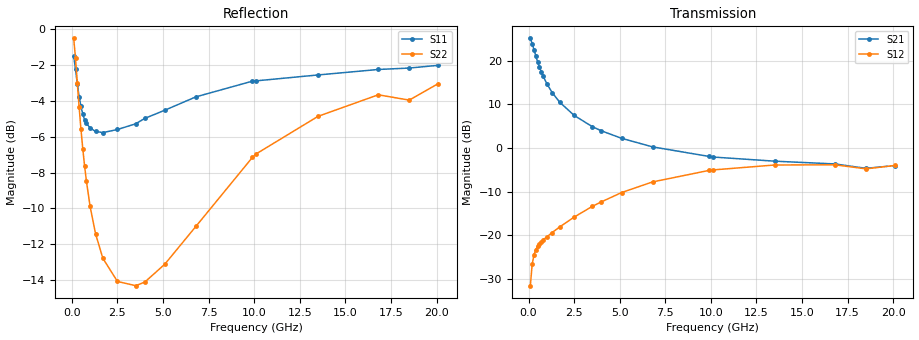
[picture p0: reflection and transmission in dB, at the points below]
!  Infineon Technologies AG
! BFR380L3 , PF131585-7, No.6, Th 09.10.01, soldered on pcb-board, measured with PP GSG850
!  Vce=4.0 V,  Ic=6.0 mA
! Common Emitter S-Parameters:  15. November 2001
#  GHz  S  MA  R  50
! f  S11  S21  S12  S22
! GHz  Mag  Ang  Mag  Ang  Mag  Ang  Mag  Ang
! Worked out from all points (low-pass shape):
!   201 points, 100 MHz to 20.1 GHz, reference 50 ohm
!   highest |S21| = 25.08 dB at 100 MHz (marker M1); lowest = -4.7 dB at 18.5 GHz (marker M2)
!   |S21| within 3 dB of the highest: start of sweep to 327.2 MHz
!   lowest |S11| = -5.8 dB at 1.7 GHz (marker M3), VSWR 3.12, Z = 16.1 - j1.68 ohm
!   |S11| at or under -10 dB: nowhere
!   |S22| runs from -14.4 to -0.5 dB; largest |S21 - S12| = 18
!   S11 on the Smith chart (normalised r, x): 100 MHz: 1.15, -3.32; 400 MHz: 0.38, -0.84; 1 GHz: 0.33, -0.25; 4 GHz: 0.31, +0.34; 9.9 GHz: 0.39, +1.12; 20.1 GHz: 0.95, +2.53
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0.1  0.8396 -30.4  17.95 159.8  0.02655 75.0  0.9416 -18.1
0.2  0.7732 -56.6  15.61 143.2  0.04655 62.5  0.8281 -32.9
0.3  0.7016 -78.0  13.29 130.5  0.05999 54.4  0.7069 -43.6
0.4  0.6472 -95.0  11.28 120.9  0.06876 49.6  0.6049 -51.3
0.5  0.6085 -108.4  9.687 113.6  0.07514 46.8  0.5249 -56.8
0.6  0.579 -119.5  8.425 107.8  0.08046 45.2  0.4631 -60.8
0.7  0.5582 -128.6  7.438 102.9  0.08457 44.4  0.4144 -64.0
0.8  0.5461 -136.3  6.635 98.8  0.0887 44.3  0.3761 -66.6
1  0.5297 -148.6  5.456 92.1  0.0961 44.8  0.3204 -70.5
1.3  0.5182 -162.3  4.295 84.1  0.1077 46.5  0.2687 -75.2
1.7  0.5144 -175.7  3.355 75.4  0.1244 48.9  0.2296 -80.9
2.5  0.5247 164.9  2.359 61.3  0.1617 51.7  0.1979 -93.0
3.5  0.5442 146.6  1.752 46.6  0.2148 51.9  0.1926 -110.5
4  0.5634 139.4  1.57 40.3  0.2419 51.0  0.1971 -121.5
5.1  0.594 124.4  1.29 27.4  0.3087 46.6  0.2212 -142.7
6.8  0.6469 105.2  1.029 11.6  0.4086 37.3  0.2817 -175.2
9.9  0.7155 79.7  0.8003 -7.2  0.5537 16.4  0.4387 141.5
10.1  0.7169 78.3  0.7878 -8.1  0.5604 15.1  0.4485 139.0
13.5  0.7446 59.8  0.7059 -22.1  0.6383 -7.5  0.571 104.7
16.8  0.7712 47.9  0.6564 -33.4  0.6419 -24.5  0.6555 80.4
18.5  0.7783 45.9  0.5846 -40.4  0.5769 -33.1  0.6336 73.9
20.1  0.7922 38.7  0.6291 -43.9  0.6312 -38.5  0.7047 62.8
